(* Logix 5000 AddOnInstructionDefinition export NORD_ADC; software revision 24.02; part 2 of 3 *)
(* tags used below, declared in another part *)
   ParameterNumber : INT;
   ParameterIndex : SINT;
   ParameterSet : SINT;
   Done : BOOL;
   Busy : BOOL;
   ReadMsg : MESSAGE;   // Read Msg to Module
   ReadTrigger : BOOL;
   ReadValue : DINT;   // Read Value from message
   WriteMsg : MESSAGE;   // Write Msg to Module
   WriteTrigger : BOOL;
   WriteValue : DINT;
   Error : BOOL;
   VFD_NotPresent : BOOL;   // VFD not present in Localbus
   EthernetDisconnected : BOOL;   // Eth. cord to Module is disconnected
   Backup : NORD_ParameterBackup;   // Parameter Backup File
   CompletionPercent : DINT;   // Backup/Restore Complete Percentage
   NewDriveDetected : BOOL;   // New Device ID detected
   NewCTUnitDetected : BOOL;
   RestoreTrigger : BOOL;   // Trigger to start restoring the VFD parameters
   AutomaticRestore : BOOL;   // Restore Automatically when New Drive is Detected
   GetID_InProcess : BOOL;
   BackupInProcess : BOOL;
   RestoreInProcess : BOOL;
   HasInternalPLC : BOOL;
   ErrorID : DINT;   // Message Error Code
   WriteValueMSG : DINT;
   Instance : INT;
   HasParamIndex : BOOL;   // Set Parameter has Indexes
   HasParamSets : BOOL;   // Set Parameter has Parameter Sets
   ReadErrorOS : BOOL;
   WriteErrorONS : BOOL;
   TrigONS1 : BOOL;
   ReadDoneOS : BOOL;
   WriteDoneONS : BOOL;
   MacAddr : SINT[6];   // MAC Address of CU/TU
   GetID_ReadTrigger : BOOL;
   BackupSM : INT;   // 0: Not Active 10: Reset indexes 20: Clear Old Backup 30: Reset Indexes 40: Prepare Read Msg 50: Read Trigger 60: Read Co
   Index : INT;
   DeviceID : STRING;   // Device ID of VFD
   RestoreSM : INT;   // 0: Not Active 10: Reset Indexes 15: # of Saved Param 20: Get RestoreParam 21: Prepare Read Msg 22: Read Trigger 23: Read
   Index1 : INT;   // Store Index: VFD
   IndexInst : INT;   // Instance Index
   RestoreParam : INT;   // Parameter Number to be Restored
   SavedParamsVFD : INT;
   BackupReadTrigger : BOOL;
   RestWriteTrig : BOOL;
   RestIndexONS : BOOL;
   RestReadTrig : BOOL;
   BackupLast : BOOL;   // Determines Backup/Restore Complete Percentage Calculation
   WriteSM : SINT;   // 0: Not Active 10: Write LEN=4 20: 1st WriteTrigger 30: Write Complete - 40: Write LEN=2 - 50: 2nd WriteTrigger 60: Write
   Class : INT;
   TrigONS2 : BOOL;
   NumOfParams : DINT;   // Number of parameters in the VFD
   WriteTriggerONS : BOOL;
   WriteTrigInternal : BOOL;   // 1st Attempt: LEN = 4 2nd Attempt: LEN = 2
   Write16Bit : BOOL;   // 0: Write LEN=4 1: Write LEN=2
   AOI_FirstScan : BOOL;   // First Scan of AOI
   Percent100ONS : BOOL;
   GetID_Done_ONS : BOOL;
   Index2 : INT;   // Store Index: CU/TU
   SavedParamsCTU : INT;
   RestoreCTU : BOOL;   // Restore CTU Parameters
   RestIndexONS2 : BOOL;
   CompPercentIndex : INT;
   StoreDevID : BOOL;
   StoreDevID_DN : BOOL;
   ResetIndexes : BOOL;
   ResetIndexDN : BOOL;
   GetRestParam : BOOL;   // Get Restore Parameter Logic
   GetRestParamDN : BOOL;   // Got Restore Param
   ResetMsgEr : BOOL;
   PerformRestoreONS : BOOL;
   RestoreFailed : BOOL;   // All writes in restore failed
   RestoreFailedONS : BOOL;
   RestoreHasWrite : BOOL;
   RestoreHasWriteONS : BOOL;
   AutomaticRestoreONS : BOOL;
   HasEthernetCard : BOOL;   // Has an ethernet card
(* NORD_ADC, continued *)

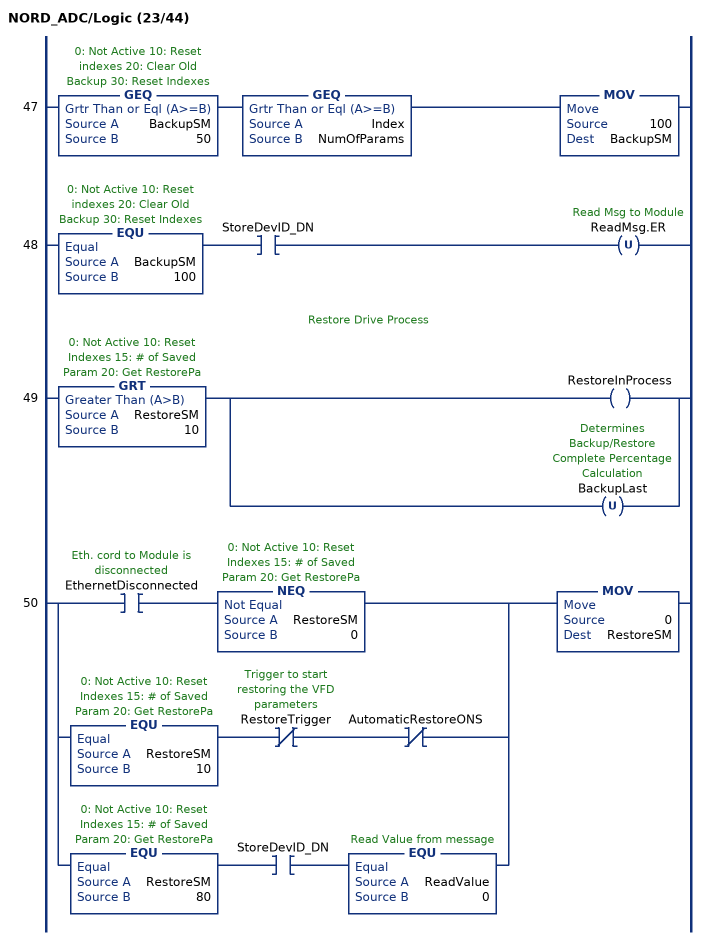
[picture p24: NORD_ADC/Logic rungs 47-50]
   47: GEQ(BackupSM,50)GEQ(Index,NumOfParams)MOV(100,BackupSM);
   48: EQU(BackupSM,100)XIC(StoreDevID_DN)OTU(ReadMsg.ER);
   // Restore Drive Process
   49: GRT(RestoreSM,10)[OTE(RestoreInProcess) ,OTU(BackupLast) ];
   50: [XIC(EthernetDisconnected) NEQ(RestoreSM,0) ,EQU(RestoreSM,10) XIO(RestoreTrigger) XIO(AutomaticRestoreONS) ,EQU(RestoreSM,80) XIC(StoreDevID_DN) EQU(ReadValue,0) ]MOV(0,RestoreSM);
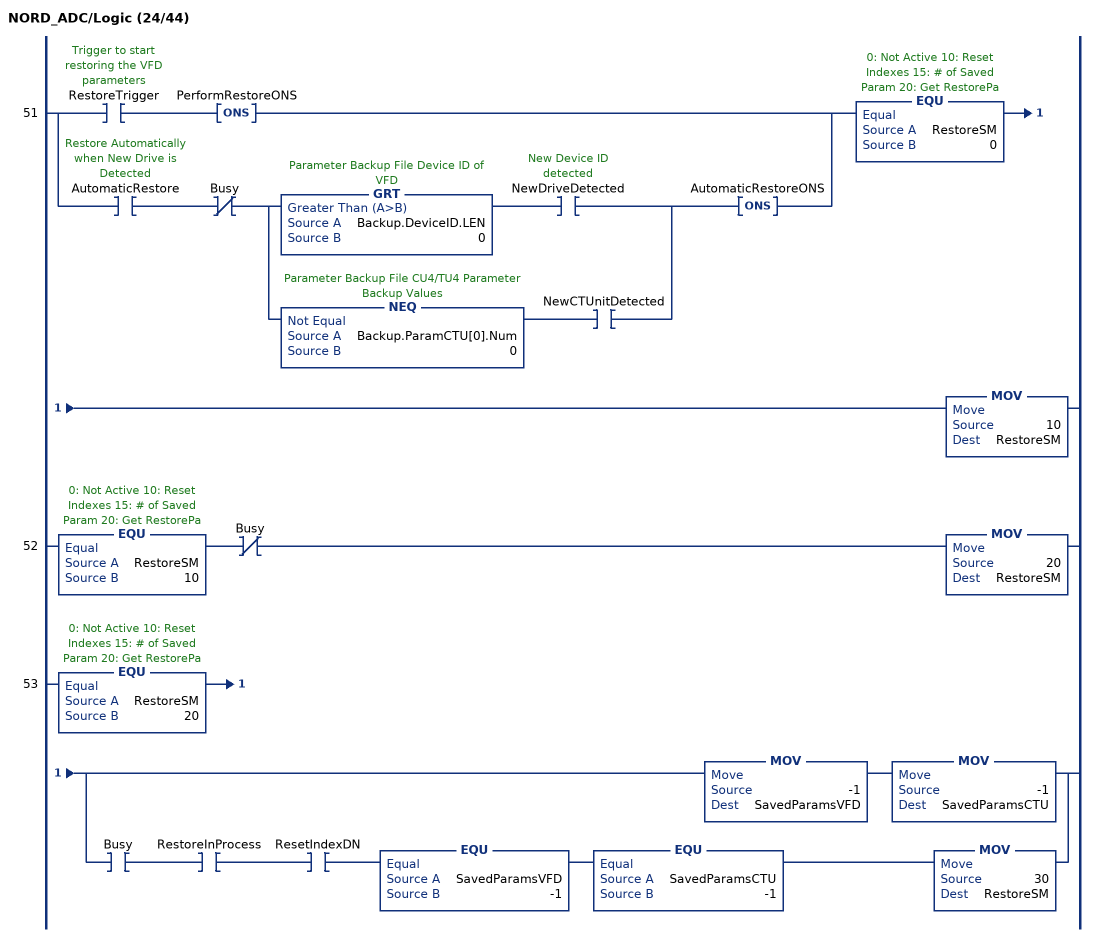
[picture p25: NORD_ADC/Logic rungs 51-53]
   51: [XIC(RestoreTrigger) ONS(PerformRestoreONS) ,XIC(AutomaticRestore) XIO(Busy) [GRT(Backup.DeviceID.LEN,0) XIC(NewDriveDetected) ,NEQ(Backup.ParamCTU[0].Num,0) XIC(NewCTUnitDetected) ] ONS(AutomaticRestoreONS) ]EQU(RestoreSM,0)MOV(10,RestoreSM);
   52: EQU(RestoreSM,10)XIO(Busy)MOV(20,RestoreSM);
   53: EQU(RestoreSM,20)[MOV(-1,SavedParamsVFD) MOV(-1,SavedParamsCTU) ,XIC(Busy) XIC(RestoreInProcess) XIC(ResetIndexDN) EQU(SavedParamsVFD,-1) EQU(SavedParamsCTU,-1) MOV(30,RestoreSM) ];
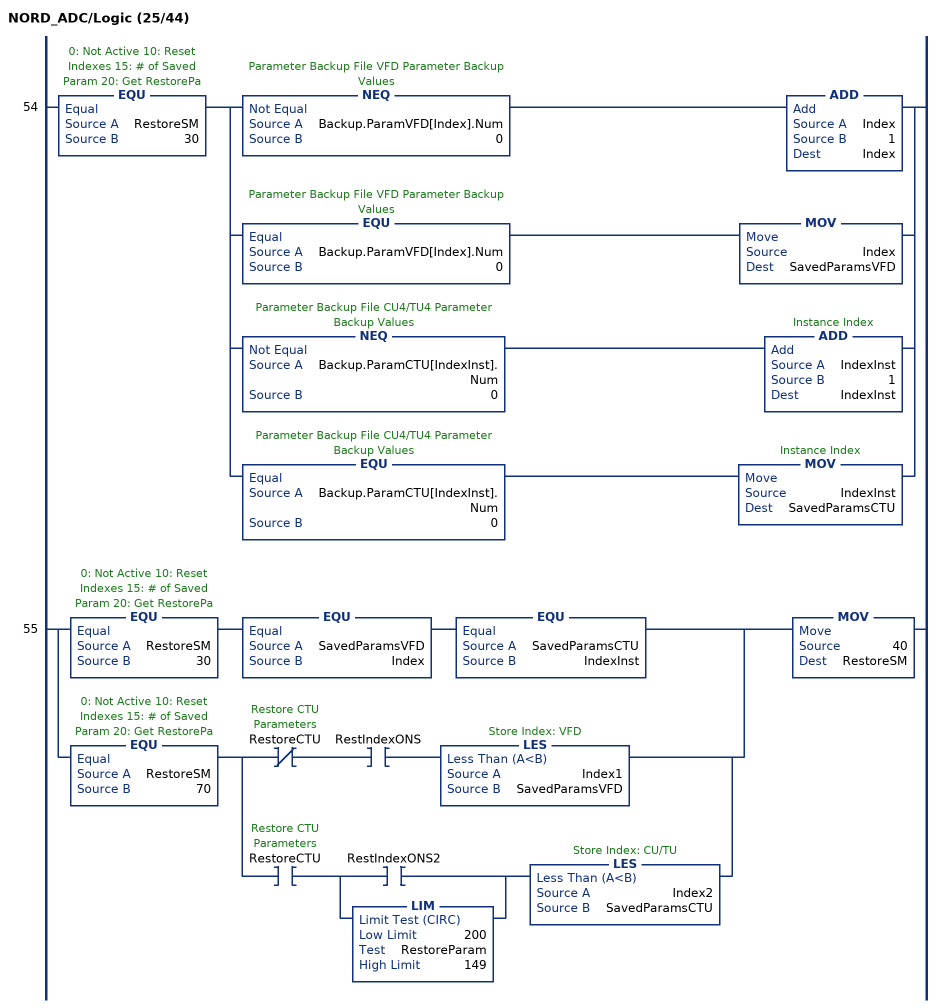
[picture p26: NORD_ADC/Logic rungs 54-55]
   54: EQU(RestoreSM,30)[[NEQ(Backup.ParamVFD[Index].Num,0) ADD(Index,1,Index) ,EQU(Backup.ParamVFD[Index].Num,0) MOV(Index,SavedParamsVFD) ] ,[NEQ(Backup.ParamCTU[IndexInst].Num,0) ADD(IndexInst,1,IndexInst) ,EQU(Backup.ParamCTU[IndexInst].Num,0) MOV(IndexInst,SavedParamsCTU) ] ];
   55: [EQU(RestoreSM,30) EQU(SavedParamsVFD,Index) EQU(SavedParamsCTU,IndexInst) ,EQU(RestoreSM,70) [XIO(RestoreCTU) XIC(RestIndexONS) LES(Index1,SavedParamsVFD) ,XIC(RestoreCTU) [XIC(RestIndexONS2) ,LIM(200,RestoreParam,149) ] LES(Index2,SavedParamsCTU) ] ]MOV(40,RestoreSM);
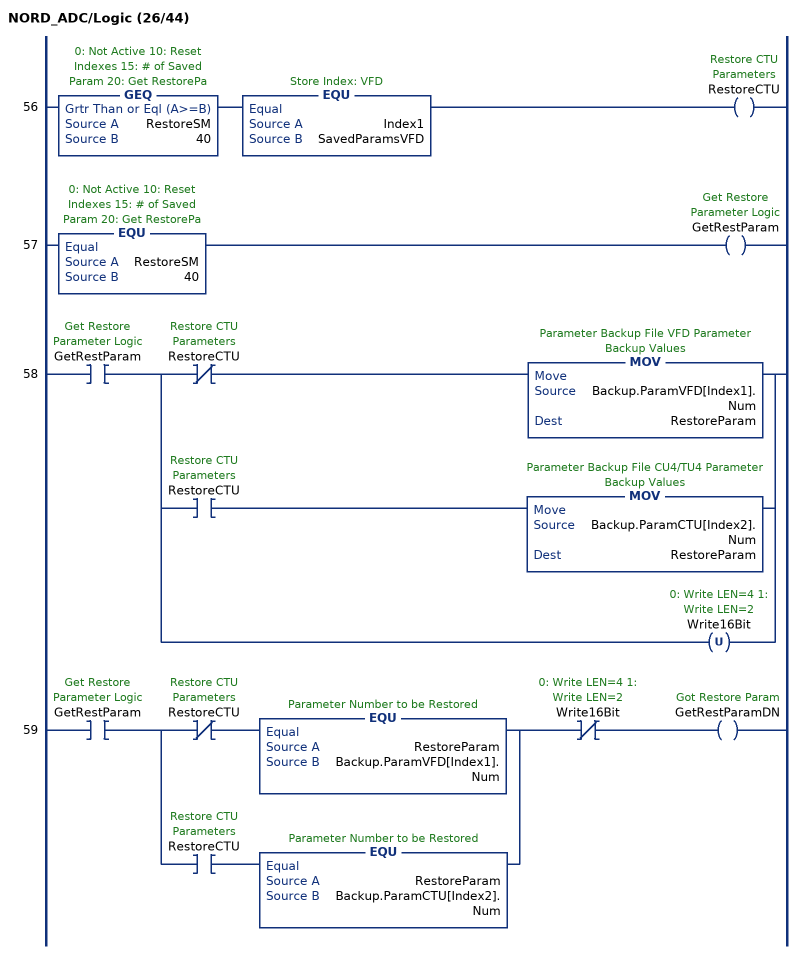
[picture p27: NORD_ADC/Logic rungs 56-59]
   56: GEQ(RestoreSM,40)EQU(Index1,SavedParamsVFD)OTE(RestoreCTU);
   57: EQU(RestoreSM,40)OTE(GetRestParam);
   58: XIC(GetRestParam)[XIO(RestoreCTU) MOV(Backup.ParamVFD[Index1].Num,RestoreParam) ,XIC(RestoreCTU) MOV(Backup.ParamCTU[Index2].Num,RestoreParam) ,OTU(Write16Bit) ];
   59: XIC(GetRestParam)[XIO(RestoreCTU) EQU(RestoreParam,Backup.ParamVFD[Index1].Num) ,XIC(RestoreCTU) EQU(RestoreParam,Backup.ParamCTU[Index2].Num) ]XIO(Write16Bit)OTE(GetRestParamDN);
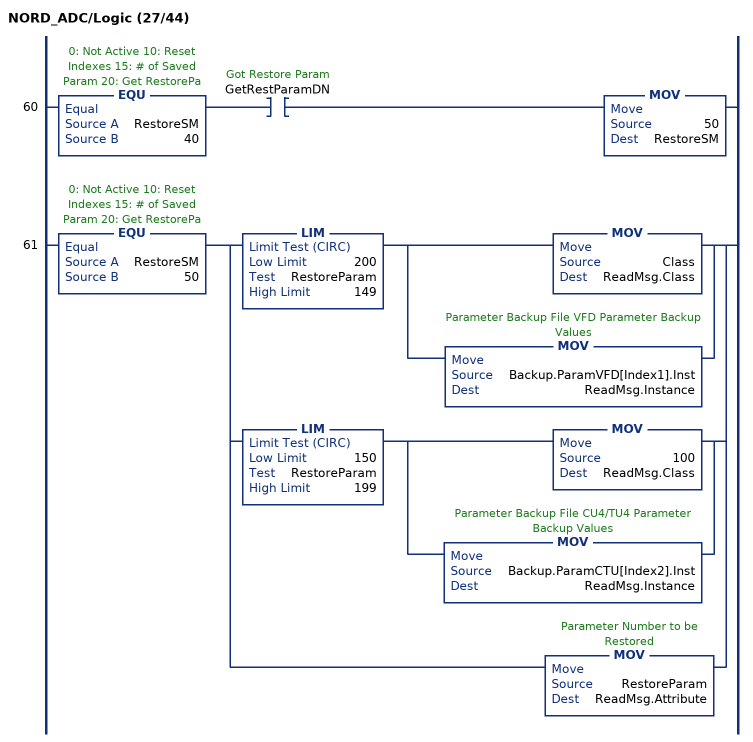
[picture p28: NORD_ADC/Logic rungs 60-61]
   60: EQU(RestoreSM,40)XIC(GetRestParamDN)MOV(50,RestoreSM);
   61: EQU(RestoreSM,50)[[LIM(200,RestoreParam,149) [MOV(Class,ReadMsg.Class) ,MOV(Backup.ParamVFD[Index1].Inst,ReadMsg.Instance) ] ,LIM(150,RestoreParam,199) [MOV(100,ReadMsg.Class) ,MOV(Backup.ParamCTU[Index2].Inst,ReadMsg.Instance) ] ] ,MOV(RestoreParam,ReadMsg.Attribute) ];
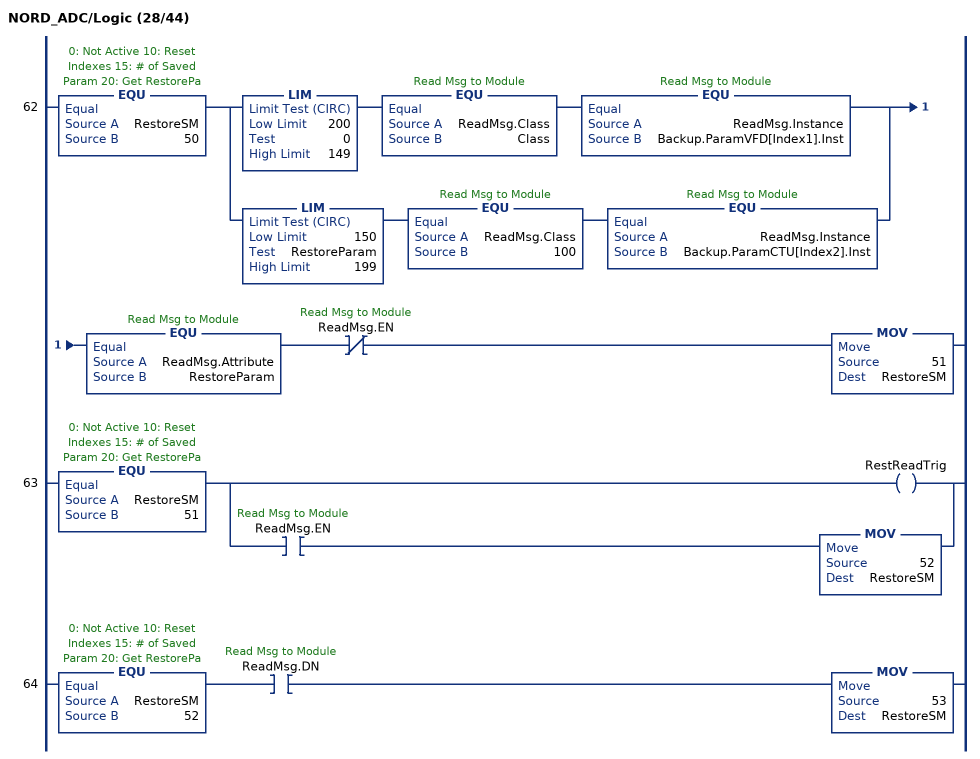
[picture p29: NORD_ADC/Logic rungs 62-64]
   62: EQU(RestoreSM,50)[LIM(200,0,149) EQU(ReadMsg.Class,Class) EQU(ReadMsg.Instance,Backup.ParamVFD[Index1].Inst) ,LIM(150,RestoreParam,199) EQU(ReadMsg.Class,100) EQU(ReadMsg.Instance,Backup.ParamCTU[Index2].Inst) ]EQU(ReadMsg.Attribute,RestoreParam)XIO(ReadMsg.EN)MOV(51,RestoreSM);
   63: EQU(RestoreSM,51)[OTE(RestReadTrig) ,XIC(ReadMsg.EN) MOV(52,RestoreSM) ];
   64: EQU(RestoreSM,52)XIC(ReadMsg.DN)MOV(53,RestoreSM);
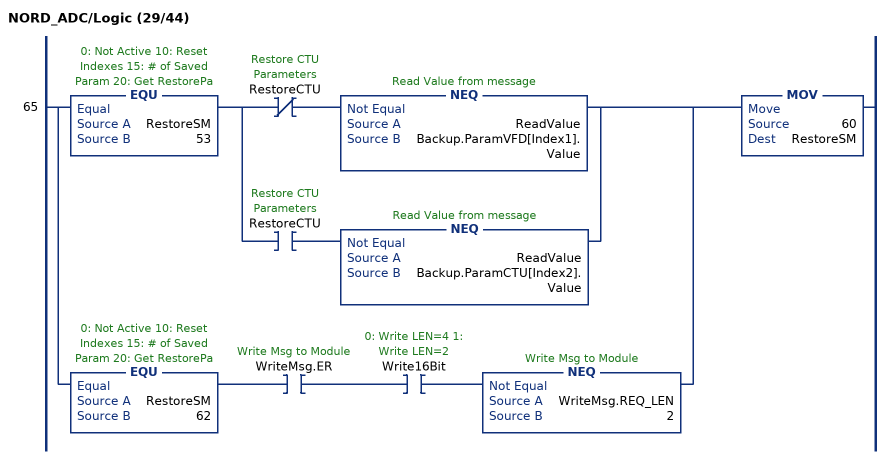
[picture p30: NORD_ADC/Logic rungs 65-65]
   65: [EQU(RestoreSM,53) [XIO(RestoreCTU) NEQ(ReadValue,Backup.ParamVFD[Index1].Value) ,XIC(RestoreCTU) NEQ(ReadValue,Backup.ParamCTU[Index2].Value) ] ,EQU(RestoreSM,62) XIC(WriteMsg.ER) XIC(Write16Bit) NEQ(WriteMsg.REQ_LEN,2) ]MOV(60,RestoreSM);
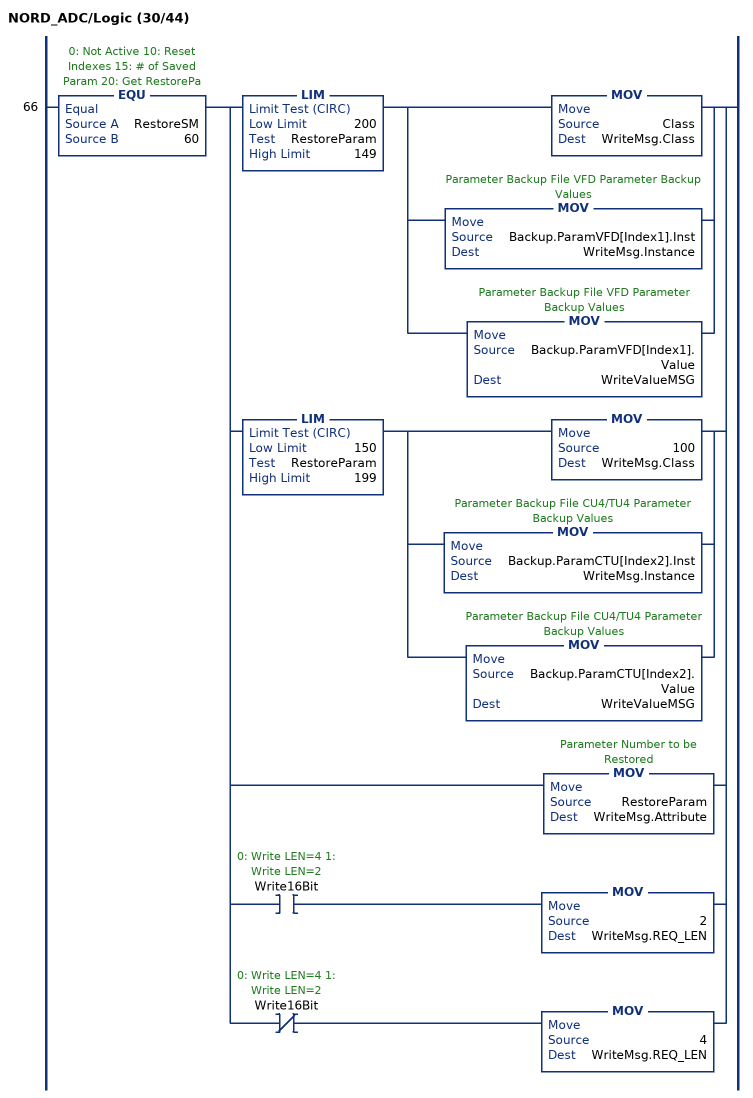
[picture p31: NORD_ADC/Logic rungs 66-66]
   66: EQU(RestoreSM,60)[[LIM(200,RestoreParam,149) [MOV(Class,WriteMsg.Class) ,[MOV(Backup.ParamVFD[Index1].Inst,WriteMsg.Instance) ,MOV(Backup.ParamVFD[Index1].Value,WriteValueMSG) ] ] ,LIM(150,RestoreParam,199) [MOV(100,WriteMsg.Class) ,MOV(Backup.ParamCTU[Index2].Inst,WriteMsg.Instance) ,MOV(Backup.ParamCTU[Index2].Value,WriteValueMSG) ] ] ,MOV(RestoreParam,WriteMsg.Attribute) ,XIC(Write16Bit) MOV(2,WriteMsg.REQ_LEN) ,XIO(Write16Bit) MOV(4,WriteMsg.REQ_LEN) ];
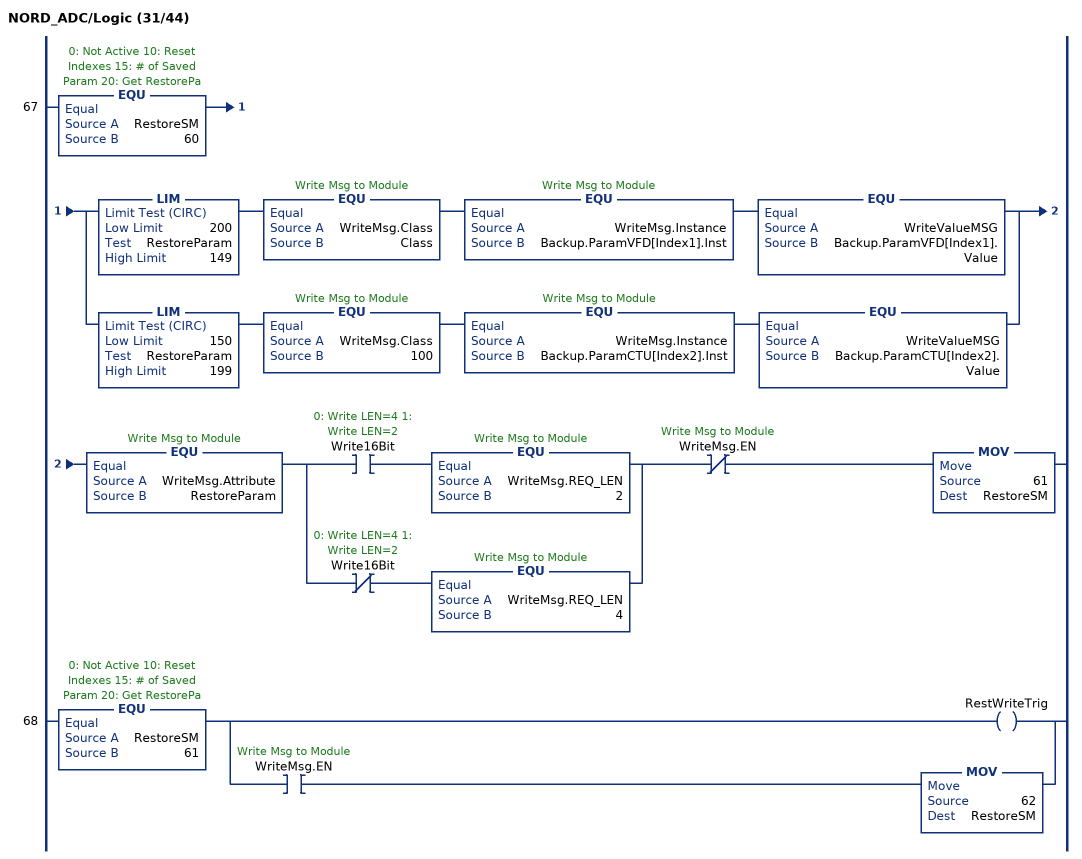
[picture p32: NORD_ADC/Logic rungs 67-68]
   67: EQU(RestoreSM,60)[LIM(200,RestoreParam,149) EQU(WriteMsg.Class,Class) EQU(WriteMsg.Instance,Backup.ParamVFD[Index1].Inst) EQU(WriteValueMSG,Backup.ParamVFD[Index1].Value) ,LIM(150,RestoreParam,199) EQU(WriteMsg.Class,100) EQU(WriteMsg.Instance,Backup.ParamCTU[Index2].Inst) EQU(WriteValueMSG,Backup.ParamCTU[Index2].Value) ]EQU(WriteMsg.Attribute,RestoreParam)[XIC(Write16Bit) EQU(WriteMsg.REQ_LEN,2) ,XIO(Write16Bit) EQU(WriteMsg.REQ_LEN,4) ]XIO(WriteMsg.EN)MOV(61,RestoreSM);
   68: EQU(RestoreSM,61)[OTE(RestWriteTrig) ,XIC(WriteMsg.EN) MOV(62,RestoreSM) ];
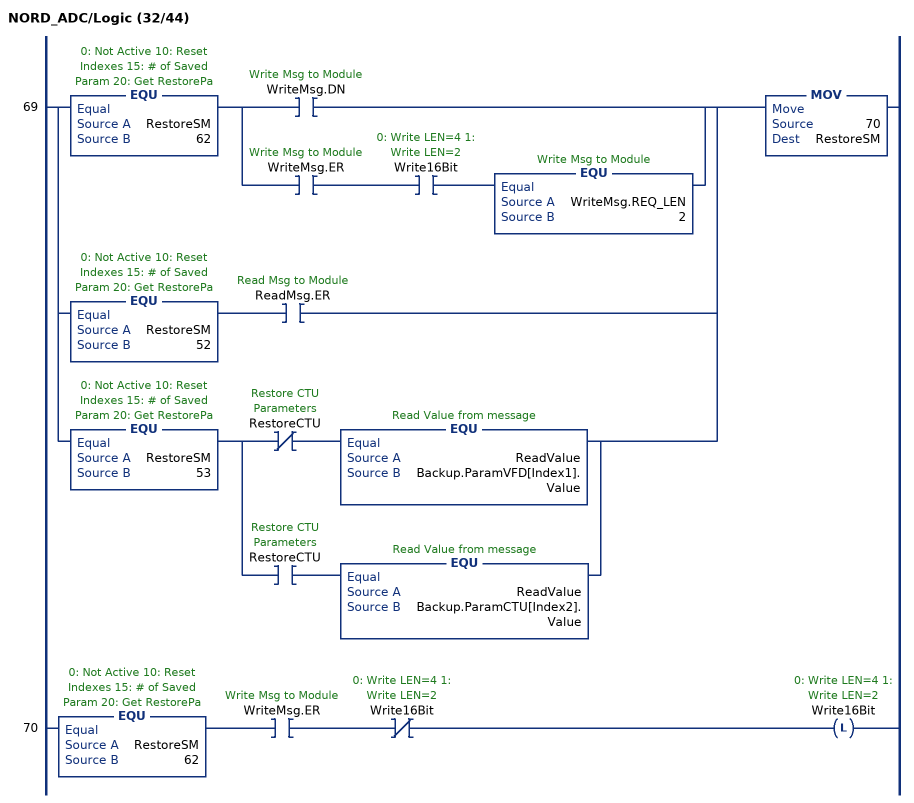
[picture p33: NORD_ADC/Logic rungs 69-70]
   69: [EQU(RestoreSM,62) [XIC(WriteMsg.DN) ,XIC(WriteMsg.ER) XIC(Write16Bit) EQU(WriteMsg.REQ_LEN,2) ] ,EQU(RestoreSM,52) XIC(ReadMsg.ER) ,EQU(RestoreSM,53) [XIO(RestoreCTU) EQU(ReadValue,Backup.ParamVFD[Index1].Value) ,XIC(RestoreCTU) EQU(ReadValue,Backup.ParamCTU[Index2].Value) ] ]MOV(70,RestoreSM);
   70: EQU(RestoreSM,62)XIC(WriteMsg.ER)XIO(Write16Bit)OTL(Write16Bit);
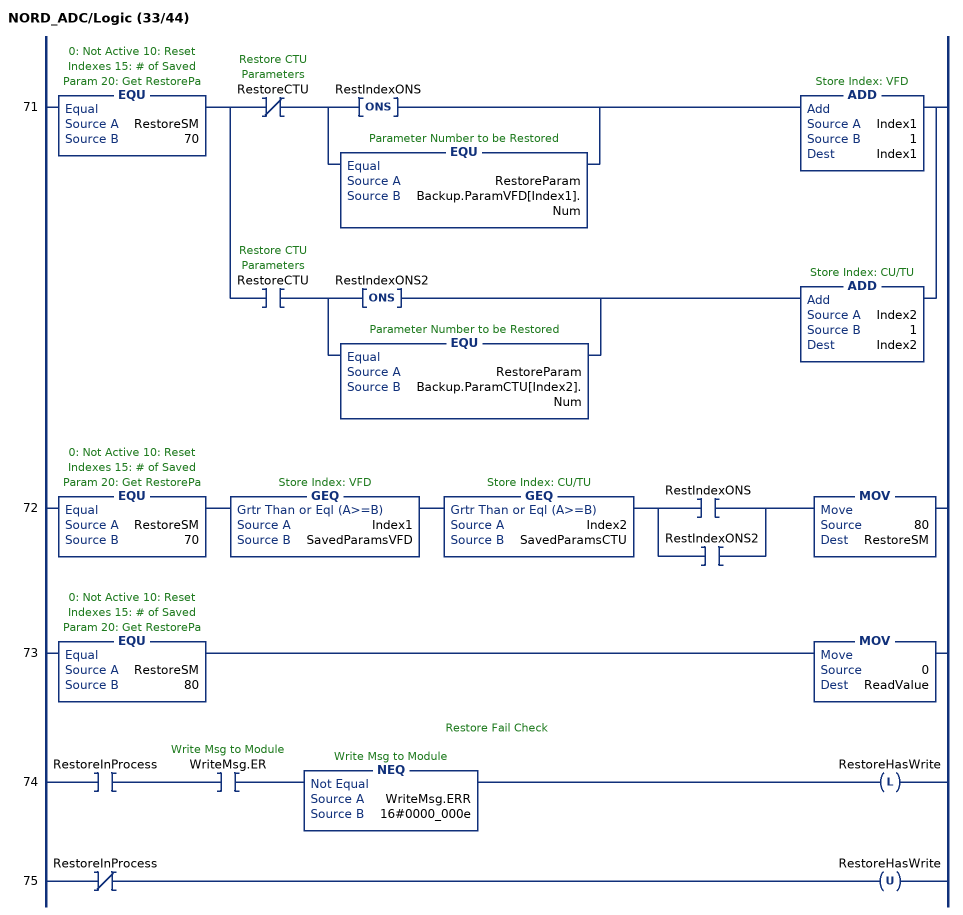
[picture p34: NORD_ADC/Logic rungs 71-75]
   71: EQU(RestoreSM,70)[XIO(RestoreCTU) [ONS(RestIndexONS) ,EQU(RestoreParam,Backup.ParamVFD[Index1].Num) ] ADD(Index1,1,Index1) ,XIC(RestoreCTU) [ONS(RestIndexONS2) ,EQU(RestoreParam,Backup.ParamCTU[Index2].Num) ] ADD(Index2,1,Index2) ];
   72: EQU(RestoreSM,70)GEQ(Index1,SavedParamsVFD)GEQ(Index2,SavedParamsCTU)[XIC(RestIndexONS) ,XIC(RestIndexONS2) ]MOV(80,RestoreSM);
   73: EQU(RestoreSM,80)MOV(0,ReadValue);
   // Restore Fail Check
   74: XIC(RestoreInProcess)XIC(WriteMsg.ER)NEQ(WriteMsg.ERR,16#0000_000e)OTL(RestoreHasWrite);
   75: XIO(RestoreInProcess)OTU(RestoreHasWrite);
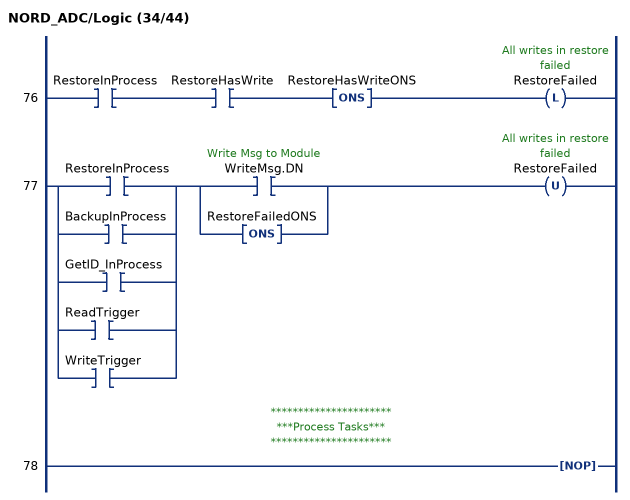
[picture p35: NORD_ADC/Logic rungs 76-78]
   76: XIC(RestoreInProcess)XIC(RestoreHasWrite)ONS(RestoreHasWriteONS)OTL(RestoreFailed);
   77: [XIC(RestoreInProcess) ,XIC(BackupInProcess) ,XIC(GetID_InProcess) ,XIC(ReadTrigger) ,XIC(WriteTrigger) ][XIC(WriteMsg.DN) ,ONS(RestoreFailedONS) ]OTU(RestoreFailed);
   // **********************
   // ***Process Tasks***
   // **********************
   78: NOP();
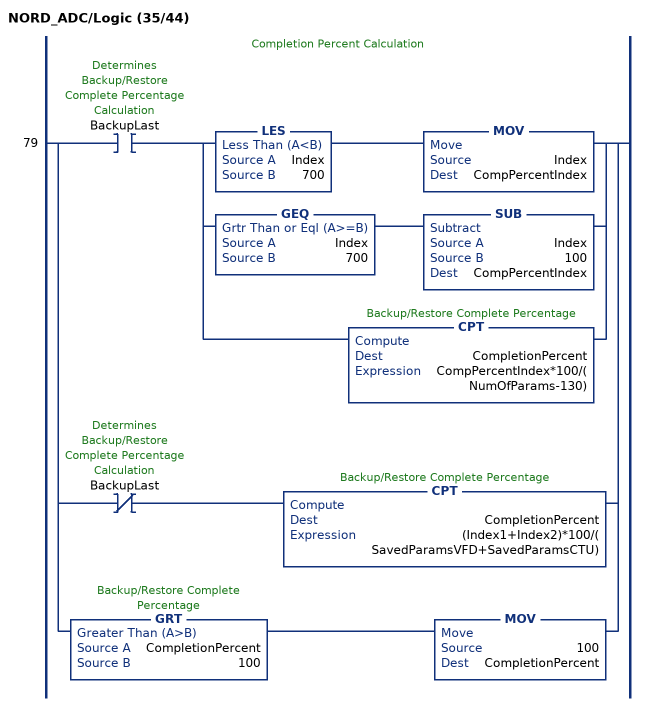
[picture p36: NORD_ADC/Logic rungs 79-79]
   // Completion Percent Calculation
   79: [XIC(BackupLast) [[LES(Index,700) MOV(Index,CompPercentIndex) ,GEQ(Index,700) SUB(Index,100,CompPercentIndex) ] ,CPT(CompletionPercent,CompPercentIndex*100/(NumOfParams-130)) ] ,XIO(BackupLast) CPT(CompletionPercent,(Index1+Index2)*100/(SavedParamsVFD+SavedParamsCTU)) ,GRT(CompletionPercent,100) MOV(100,CompletionPercent) ];
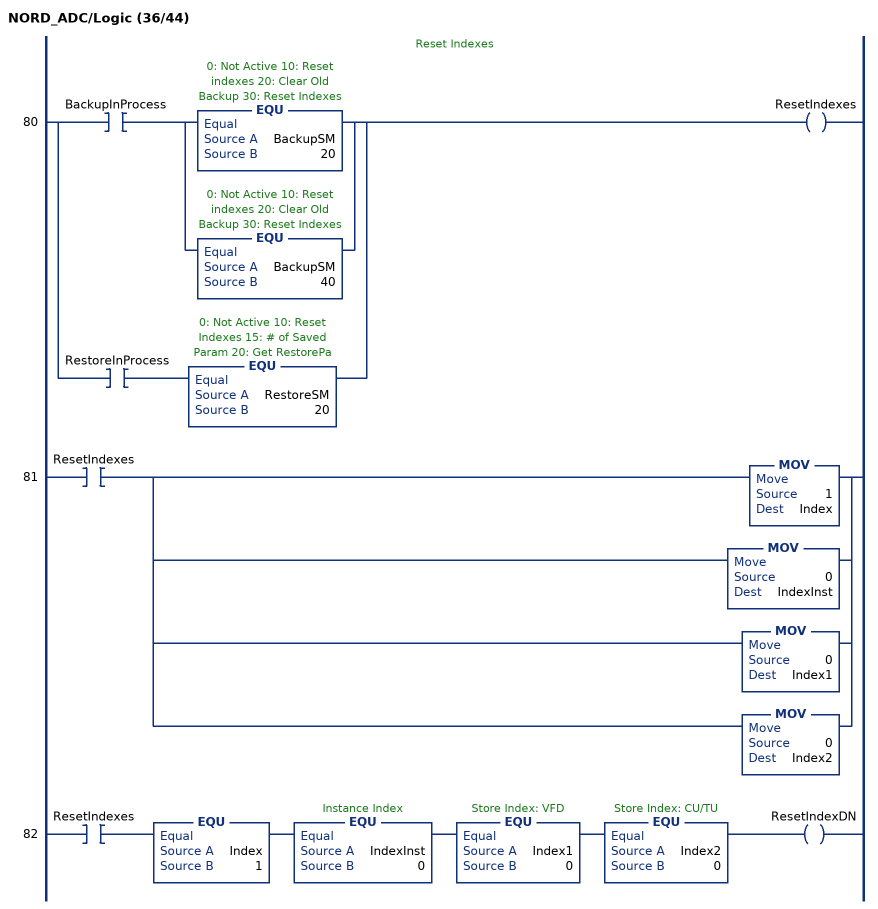
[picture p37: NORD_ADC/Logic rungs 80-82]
   // Reset Indexes
   80: [XIC(BackupInProcess) [EQU(BackupSM,20) ,EQU(BackupSM,40) ] ,XIC(RestoreInProcess) EQU(RestoreSM,20) ]OTE(ResetIndexes);
   81: XIC(ResetIndexes)[MOV(1,Index) ,MOV(0,IndexInst) ,MOV(0,Index1) ,MOV(0,Index2) ];
   82: XIC(ResetIndexes)EQU(Index,1)EQU(IndexInst,0)EQU(Index1,0)EQU(Index2,0)OTE(ResetIndexDN);
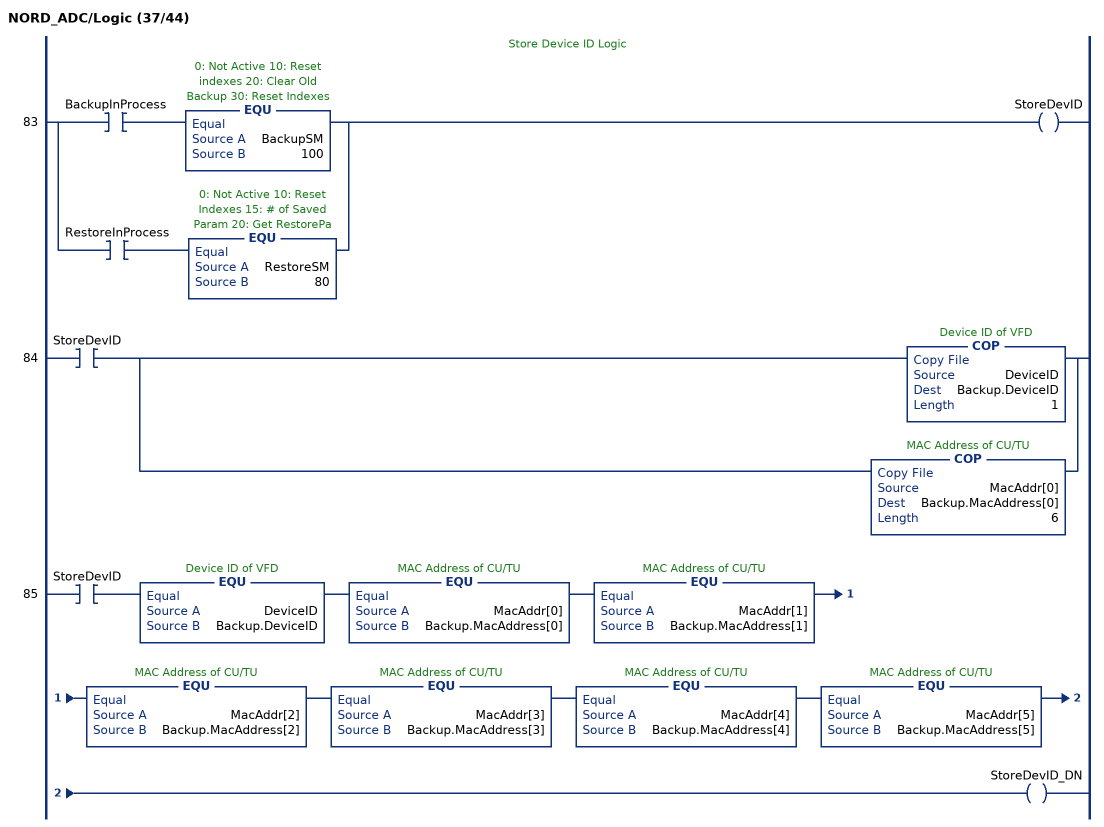
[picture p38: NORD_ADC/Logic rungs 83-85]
   // Store Device ID Logic
   83: [XIC(BackupInProcess) EQU(BackupSM,100) ,XIC(RestoreInProcess) EQU(RestoreSM,80) ]OTE(StoreDevID);
   84: XIC(StoreDevID)[COP(DeviceID,Backup.DeviceID,1) ,COP(MacAddr[0],Backup.MacAddress[0],6) ];
   85: XIC(StoreDevID)EQU(DeviceID,Backup.DeviceID)EQU(MacAddr[0],Backup.MacAddress[0])EQU(MacAddr[1],Backup.MacAddress[1])EQU(MacAddr[2],Backup.MacAddress[2])EQU(MacAddr[3],Backup.MacAddress[3])EQU(MacAddr[4],Backup.MacAddress[4])EQU(MacAddr[5],Backup.MacAddress[5])OTE(StoreDevID_DN);
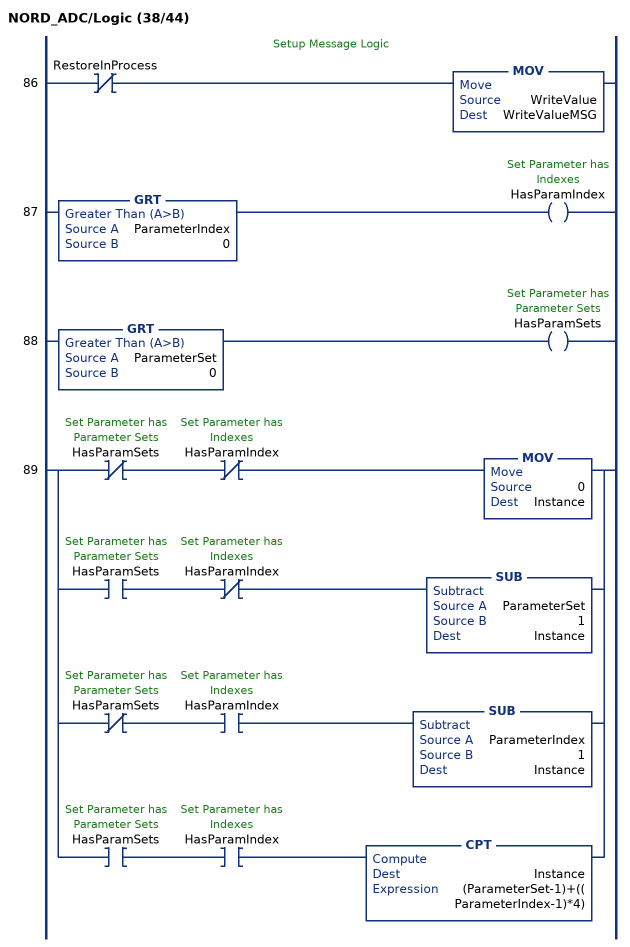
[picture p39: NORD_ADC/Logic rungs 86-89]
   // Setup Message Logic
   86: XIO(RestoreInProcess)MOV(WriteValue,WriteValueMSG);
   87: GRT(ParameterIndex,0)OTE(HasParamIndex);
   88: GRT(ParameterSet,0)OTE(HasParamSets);
   89: [XIO(HasParamSets) XIO(HasParamIndex) MOV(0,Instance) ,XIC(HasParamSets) XIO(HasParamIndex) SUB(ParameterSet,1,Instance) ,XIO(HasParamSets) XIC(HasParamIndex) SUB(ParameterIndex,1,Instance) ,XIC(HasParamSets) XIC(HasParamIndex) CPT(Instance,(ParameterSet-1)+((ParameterIndex-1)*4)) ];
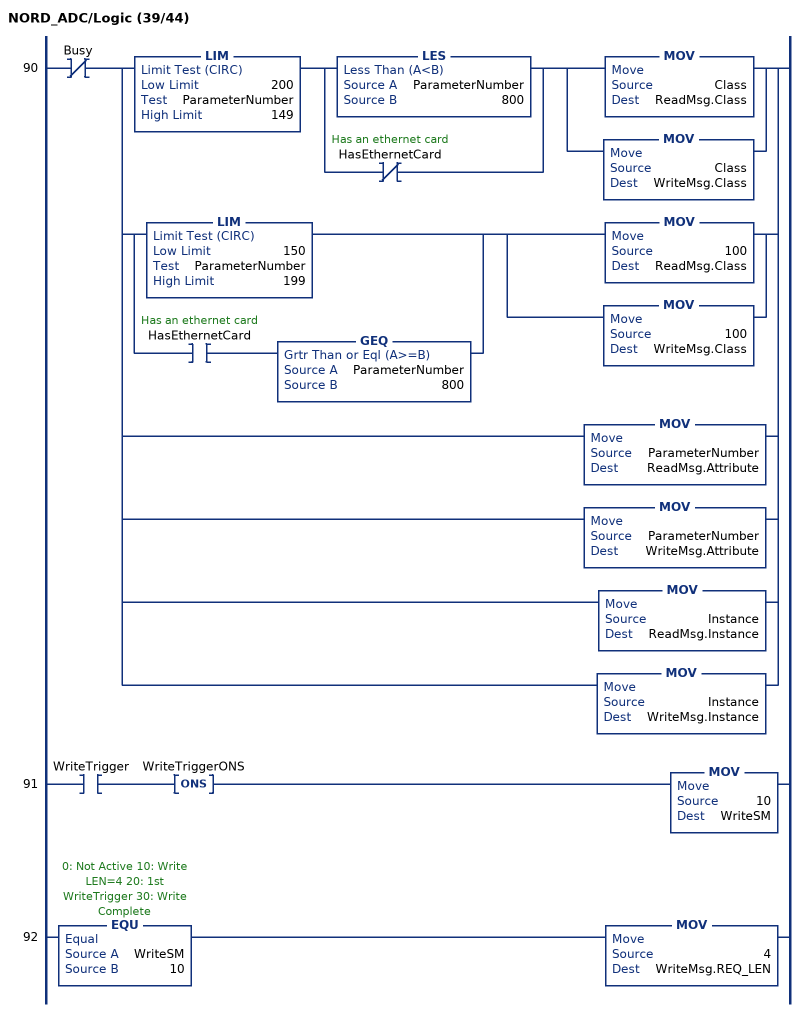
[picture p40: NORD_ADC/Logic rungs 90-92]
   90: XIO(Busy)[[LIM(200,ParameterNumber,149) [LES(ParameterNumber,800) ,XIO(HasEthernetCard) ] [MOV(Class,ReadMsg.Class) ,MOV(Class,WriteMsg.Class) ] ,[LIM(150,ParameterNumber,199) ,XIC(HasEthernetCard) GEQ(ParameterNumber,800) ] [MOV(100,ReadMsg.Class) ,MOV(100,WriteMsg.Class) ] ] ,[MOV(ParameterNumber,ReadMsg.Attribute) ,MOV(ParameterNumber,WriteMsg.Attribute) ] ,[MOV(Instance,ReadMsg.Instance) ,MOV(Instance,WriteMsg.Instance) ] ];
   91: XIC(WriteTrigger)ONS(WriteTriggerONS)MOV(10,WriteSM);
   92: EQU(WriteSM,10)MOV(4,WriteMsg.REQ_LEN);
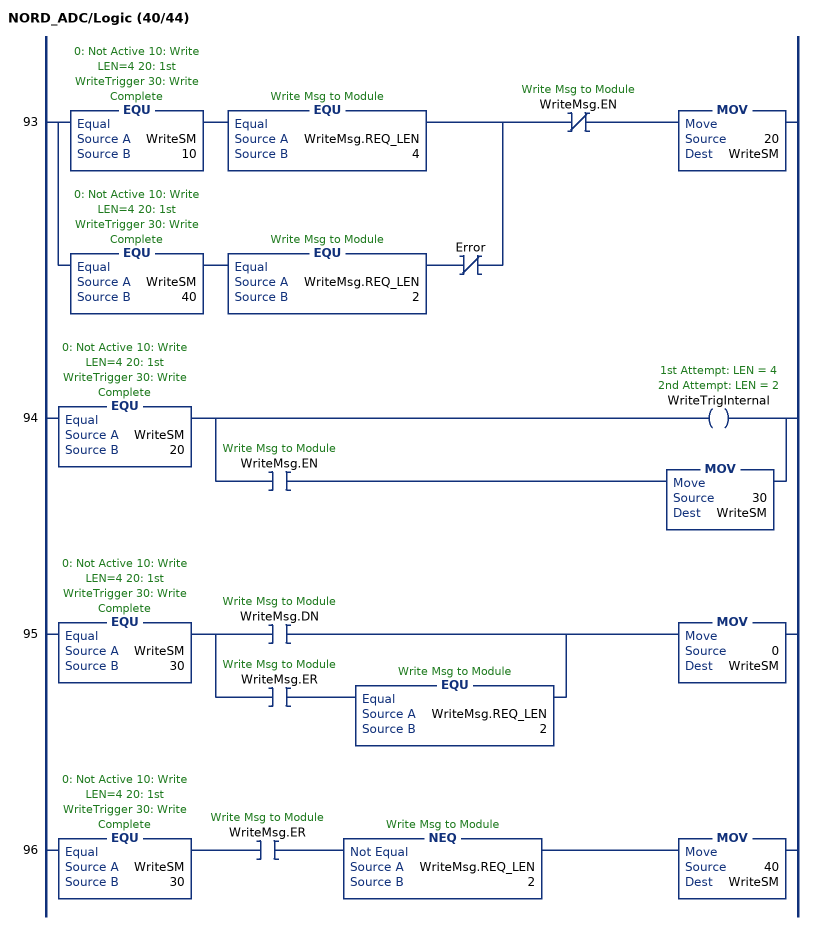
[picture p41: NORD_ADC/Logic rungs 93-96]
   93: [EQU(WriteSM,10) EQU(WriteMsg.REQ_LEN,4) ,EQU(WriteSM,40) EQU(WriteMsg.REQ_LEN,2) XIO(Error) ]XIO(WriteMsg.EN)MOV(20,WriteSM);
   94: EQU(WriteSM,20)[OTE(WriteTrigInternal) ,XIC(WriteMsg.EN) MOV(30,WriteSM) ];
   95: EQU(WriteSM,30)[XIC(WriteMsg.DN) ,XIC(WriteMsg.ER) EQU(WriteMsg.REQ_LEN,2) ]MOV(0,WriteSM);
   96: EQU(WriteSM,30)XIC(WriteMsg.ER)NEQ(WriteMsg.REQ_LEN,2)MOV(40,WriteSM);
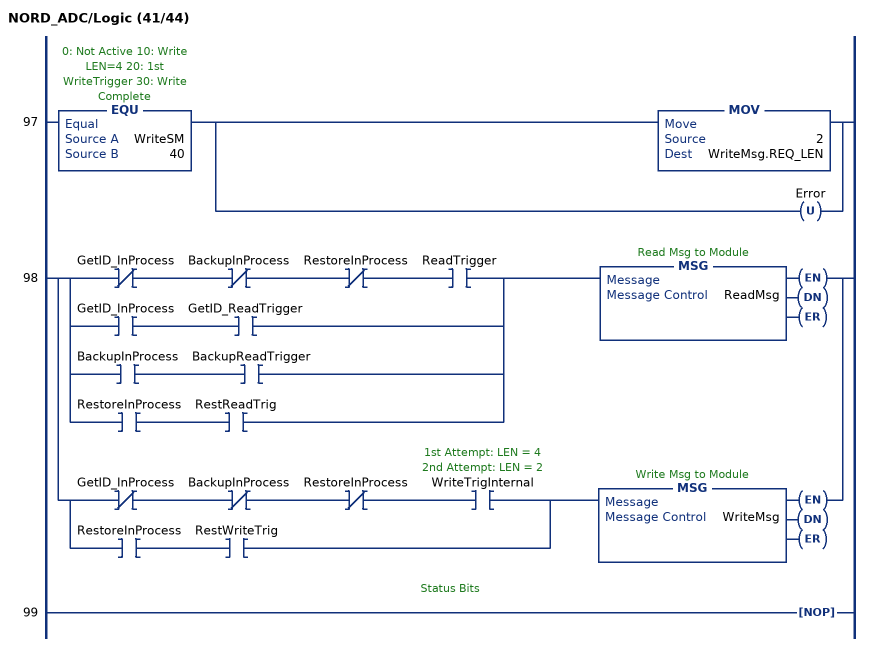
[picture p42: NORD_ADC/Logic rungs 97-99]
   97: EQU(WriteSM,40)[MOV(2,WriteMsg.REQ_LEN) ,OTU(Error) ];
   98: [[XIO(GetID_InProcess) XIO(BackupInProcess) XIO(RestoreInProcess) XIC(ReadTrigger) ,XIC(GetID_InProcess) XIC(GetID_ReadTrigger) ,XIC(BackupInProcess) XIC(BackupReadTrigger) ,XIC(RestoreInProcess) XIC(RestReadTrig) ] MSG(ReadMsg) ,[XIO(GetID_InProcess) XIO(BackupInProcess) XIO(RestoreInProcess) XIC(WriteTrigInternal) ,XIC(RestoreInProcess) XIC(RestWriteTrig) ] MSG(WriteMsg) ];
   // Status Bits
   99: NOP();
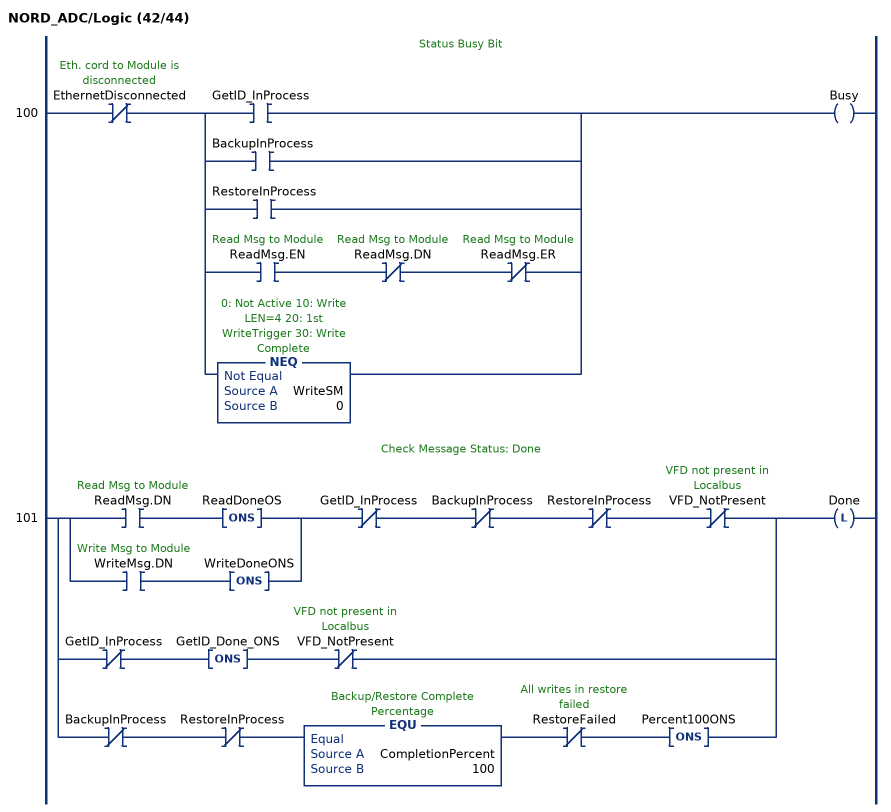
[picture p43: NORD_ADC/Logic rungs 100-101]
   // Status Busy Bit
   100: XIO(EthernetDisconnected)[XIC(GetID_InProcess) ,XIC(BackupInProcess) ,XIC(RestoreInProcess) ,XIC(ReadMsg.EN) XIO(ReadMsg.DN) XIO(ReadMsg.ER) ,NEQ(WriteSM,0) ]OTE(Busy);
   // Check Message Status: Done
   101: [[XIC(ReadMsg.DN) ONS(ReadDoneOS) ,XIC(WriteMsg.DN) ONS(WriteDoneONS) ] XIO(GetID_InProcess) XIO(BackupInProcess) XIO(RestoreInProcess) XIO(VFD_NotPresent) ,XIO(GetID_InProcess) ONS(GetID_Done_ONS) XIO(VFD_NotPresent) ,XIO(BackupInProcess) XIO(RestoreInProcess) EQU(CompletionPercent,100) XIO(RestoreFailed) ONS(Percent100ONS) ]OTL(Done);
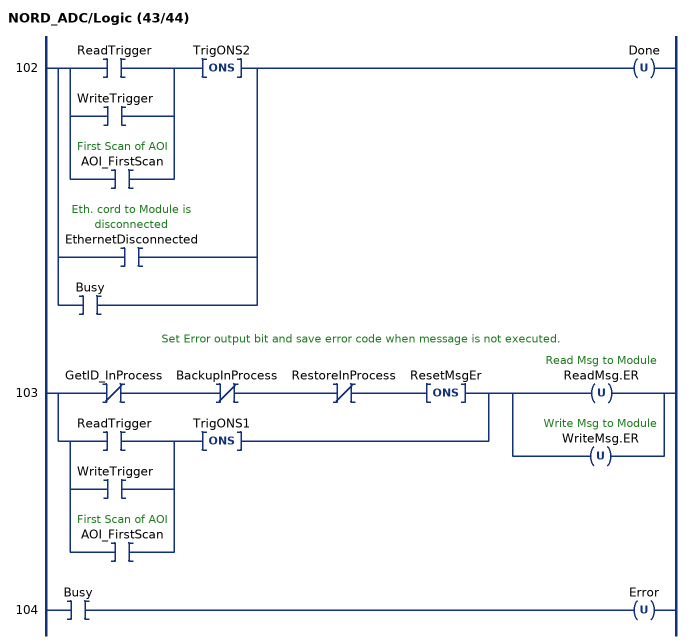
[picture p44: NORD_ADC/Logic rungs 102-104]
   102: [[XIC(ReadTrigger) ,XIC(WriteTrigger) ,XIC(AOI_FirstScan) ] ONS(TrigONS2) ,XIC(EthernetDisconnected) ,XIC(Busy) ]OTU(Done);
   // Set Error output bit and save error code when message is not executed.
   103: [XIO(GetID_InProcess) XIO(BackupInProcess) XIO(RestoreInProcess) ONS(ResetMsgEr) ,[XIC(ReadTrigger) ,XIC(WriteTrigger) ,XIC(AOI_FirstScan) ] ONS(TrigONS1) ][OTU(ReadMsg.ER) ,OTU(WriteMsg.ER) ];
   104: XIC(Busy)OTU(Error);
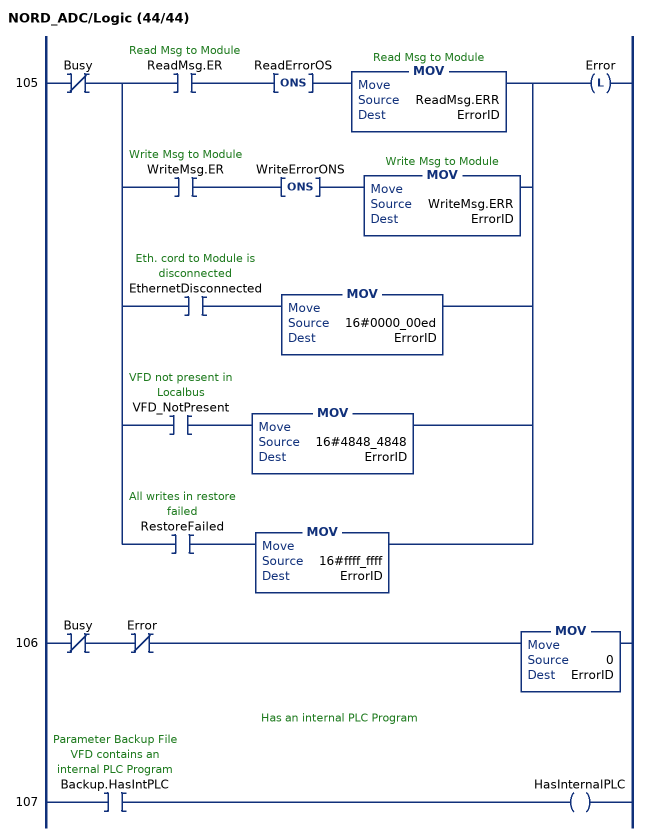
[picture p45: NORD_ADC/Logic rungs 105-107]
   105: XIO(Busy)[XIC(ReadMsg.ER) ONS(ReadErrorOS) MOV(ReadMsg.ERR,ErrorID) ,XIC(WriteMsg.ER) ONS(WriteErrorONS) MOV(WriteMsg.ERR,ErrorID) ,XIC(EthernetDisconnected) MOV(16#0000_00ed,ErrorID) ,XIC(VFD_NotPresent) MOV(16#4848_4848,ErrorID) ,XIC(RestoreFailed) MOV(16#ffff_ffff,ErrorID) ]OTL(Error);
   106: XIO(Busy)XIO(Error)MOV(0,ErrorID);
   // Has an internal PLC Program
   107: XIC(Backup.HasIntPLC)OTE(HasInternalPLC);
END_ROUTINE
